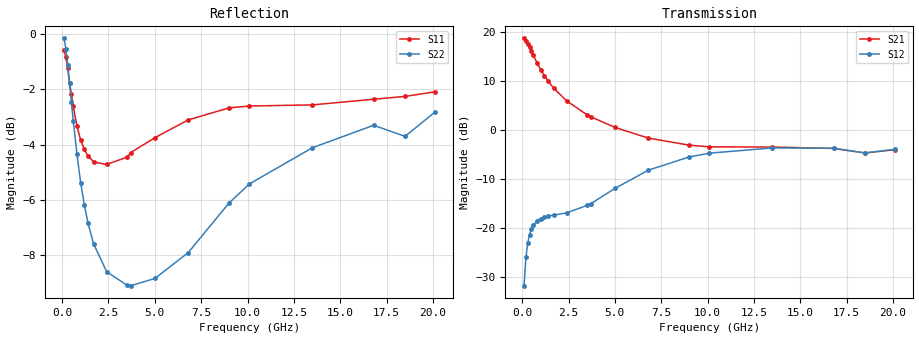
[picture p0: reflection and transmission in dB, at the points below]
!  Infineon Technologies AG
! BFR380L3 , PF131585-7, No.6, Th 09.10.01, soldered on pcb-board, measured with PP GSG850
!  Vce=6.0 V,  Ic=2.5 mA
! Common Emitter S-Parameters:  15. November 2001
#  GHz  S  MA  R  50
! f  S11  S21  S12  S22
! GHz  Mag  Ang  Mag  Ang  Mag  Ang  Mag  Ang
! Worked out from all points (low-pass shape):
!   201 points, 100 MHz to 20.1 GHz, reference 50 ohm
!   highest |S21| = 18.64 dB at 100 MHz (marker M1); lowest = -4.7 dB at 18.5 GHz (marker M2)
!   |S21| within 3 dB of the highest: start of sweep to 545.6 MHz
!   lowest |S11| = -4.7 dB at 2.4 GHz (marker M3), VSWR 3.77, Z = 13.3 - j0.144 ohm
!   |S11| at or under -10 dB: nowhere
!   |S22| runs from -9.1 to -0.2 dB; largest |S21 - S12| = 8.6
!   S11 on the Smith chart (normalised r, x): 100 MHz: 1.31, -6.09; 500 MHz: 0.31, -1.20; 1.2 GHz: 0.28, -0.39; 3.7 GHz: 0.26, +0.23; 9 GHz: 0.32, +1.03; 20.1 GHz: 0.99, +2.52
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0.1  0.9364 -17.9  8.554 167.5  0.02607 78.4  0.9812 -9.2
0.2  0.9062 -34.6  8.048 156.2  0.05047 70.6  0.9399 -17.8
0.3  0.8658 -50.7  7.527 145.6  0.07073 62.4  0.8796 -25.2
0.4  0.8165 -64.7  6.921 136.4  0.08614 55.5  0.8146 -31.3
0.5  0.778 -77.3  6.317 128.4  0.09806 50.3  0.7529 -36.3
0.6  0.7394 -88.6  5.759 121.5  0.107 45.9  0.6964 -40.2
0.8  0.681 -107.1  4.828 110.3  0.1189 39.6  0.6055 -46.0
1  0.6429 -121.9  4.11 101.5  0.1257 35.8  0.5385 -50.0
1.2  0.6183 -134.3  3.565 94.1  0.1301 33.5  0.4905 -53.0
1.4  0.6016 -144.4  3.14 87.8  0.133 32.3  0.4547 -55.6
1.7  0.5871 -157.1  2.666 79.7  0.1362 32.1  0.4174 -59.2
2.4  0.5809 -179.6  1.978 64.2  0.1434 35.9  0.372 -67.8
3.5  0.5988 155.3  1.428 45.3  0.171 46.0  0.3514 -84.9
3.7  0.6102 151.9  1.364 42.6  0.1779 47.4  0.3509 -89.0
5  0.6492 130.2  1.063 26.2  0.2542 52.0  0.3616 -114.2
6.8  0.699 106.5  0.8283 11.1  0.3898 44.5  0.4026 -153.2
8.999999  0.7349 85.1  0.7015 0.9  0.5312 27.5  0.4947 166.1
10.1  0.7407 76.6  0.6742 -3.0  0.5811 18.4  0.5356 148.3
13.5  0.7441 58.5  0.6704 -16.4  0.6575 -6.5  0.6227 108.1
16.8  0.7618 47.3  0.6493 -29.2  0.6521 -24.0  0.6836 82.1
18.5  0.7709 45.6  0.5829 -37.0  0.5844 -32.7  0.6529 75.4
20.1  0.7855 38.5  0.6303 -40.9  0.6361 -38.1  0.7217 64.1
